VERSION 5.8 ;
BUSBITCHARS "[]" ;
DIVIDERCHAR "/" ;

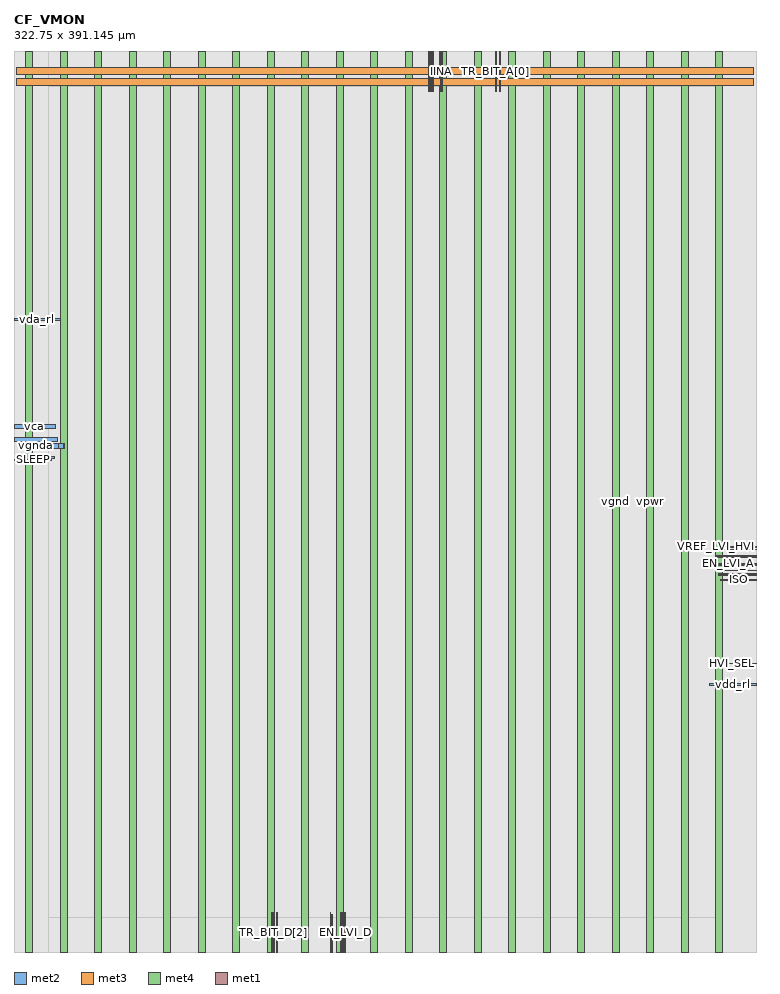
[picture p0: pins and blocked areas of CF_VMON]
MACRO CF_VMON
  CLASS BLOCK ;
  ORIGIN 0 0 ;
  FOREIGN CF_VMON 0 0 ;
  SIZE 322.75 BY 391.145 ;
  PIN vgnd
    DIRECTION INPUT ;
    USE GROUND ;
    PORT
      LAYER met2 ;
        RECT 15 218.8 19.265 220.8 ;
        RECT 15 218.8 21.79 220.8 ;
      LAYER met3 ;
        RECT 21.31 218.8 21.79 220.8 ;
        RECT 1.23 376.645 321.52 379.745 ;
      LAYER met4 ;
        RECT 20 0 23.1 391.145 ;
        RECT 50 0 53.1 391.145 ;
        RECT 80 0 83.1 391.145 ;
        RECT 110 0 113.1 391.145 ;
        RECT 140 0 143.1 391.145 ;
        RECT 170 0 173.1 391.145 ;
        RECT 200 0 203.1 391.145 ;
        RECT 230 0 233.1 391.145 ;
        RECT 260 0 263.1 391.145 ;
        RECT 290 0 293.1 391.145 ;
    END
  END vgnd
  PIN vgnda
    DIRECTION INOUT ;
    USE SIGNAL ;
    PORT
      LAYER met2 ;
        RECT 0 221.72 19.1 223.72 ;
    END
  END vgnda
  PIN vdd_rl
    DIRECTION INOUT ;
    USE SIGNAL ;
    PORT
      LAYER met2 ;
        RECT 302.455 115.665 322.75 116.565 ;
    END
  END vdd_rl
  PIN vda_rl
    DIRECTION INOUT ;
    USE SIGNAL ;
    PORT
      LAYER met2 ;
        RECT 0 274.325 20.39 275.225 ;
    END
  END vda_rl
  PIN vpwr
    DIRECTION INPUT ;
    USE POWER ;
    PORT
      LAYER met2 ;
        RECT 15 214.435 17.475 215.395 ;
        RECT 6.31 214.435 17.475 215.395 ;
      LAYER met3 ;
        RECT 6.31 214.435 6.79 215.395 ;
        RECT 1.23 381.445 321.52 384.545 ;
      LAYER met4 ;
        RECT 5 0 8.1 391.145 ;
        RECT 35 0 38.1 391.145 ;
        RECT 65 0 68.1 391.145 ;
        RECT 95 0 98.1 391.145 ;
        RECT 125 0 128.1 391.145 ;
        RECT 155 0 158.1 391.145 ;
        RECT 185 0 188.1 391.145 ;
        RECT 215 0 218.1 391.145 ;
        RECT 245 0 248.1 391.145 ;
        RECT 275 0 278.1 391.145 ;
        RECT 305 0 308.1 391.145 ;
    END
  END vpwr
  PIN vca
    DIRECTION INOUT ;
    USE SIGNAL ;
    PORT
      LAYER met2 ;
        RECT 0 227.51 18.245 229.43 ;
    END
  END vca
  PIN PRES_D_OUT
    DIRECTION OUTPUT ;
    USE SIGNAL ;
    PORT
      LAYER met2 ;
        RECT 305.335 171.55 322.75 171.79 ;
    END
  END PRES_D_OUT
  PIN PRES_A_OUT
    DIRECTION OUTPUT ;
    USE SIGNAL ;
    PORT
      LAYER met2 ;
        RECT 305.4 168.595 322.75 168.835 ;
    END
  END PRES_A_OUT
  PIN LVI_D_OUT
    DIRECTION OUTPUT ;
    USE SIGNAL ;
    PORT
      LAYER met2 ;
        RECT 306.09 165.64 322.75 165.88 ;
    END
  END LVI_D_OUT
  PIN LVI_A_OUT
    DIRECTION OUTPUT ;
    USE SIGNAL ;
    PORT
      LAYER met2 ;
        RECT 306.055 163.7 322.75 163.94 ;
    END
  END LVI_A_OUT
  PIN HVI_OUT
    DIRECTION OUTPUT ;
    USE SIGNAL ;
    PORT
      LAYER met2 ;
        RECT 306.055 164.16 322.75 164.4 ;
    END
  END HVI_OUT
  PIN TR_BIT_D[3]
    DIRECTION INPUT ;
    USE SIGNAL ;
    PORT
      LAYER met1 ;
        RECT 112.115 0 112.255 17.15 ;
    END
  END TR_BIT_D[3]
  PIN TR_BIT_D[2]
    DIRECTION INPUT ;
    USE SIGNAL ;
    PORT
      LAYER met1 ;
        RECT 112.555 0 112.695 17.15 ;
    END
  END TR_BIT_D[2]
  PIN TR_BIT_D[1]
    DIRECTION INPUT ;
    USE SIGNAL ;
    PORT
      LAYER met1 ;
        RECT 113.875 0 114.015 17.15 ;
    END
  END TR_BIT_D[1]
  PIN TR_BIT_D[0]
    DIRECTION INPUT ;
    USE SIGNAL ;
    PORT
      LAYER met1 ;
        RECT 114.315 0 114.455 17.15 ;
    END
  END TR_BIT_D[0]
  PIN TR_BIT_A[3]
    DIRECTION INPUT ;
    USE SIGNAL ;
    PORT
      LAYER met1 ;
        RECT 211.44 373.995 211.58 391.145 ;
    END
  END TR_BIT_A[3]
  PIN TR_BIT_A[2]
    DIRECTION INPUT ;
    USE SIGNAL ;
    PORT
      LAYER met1 ;
        RECT 211 373.995 211.14 391.145 ;
    END
  END TR_BIT_A[2]
  PIN TR_BIT_A[1]
    DIRECTION INPUT ;
    USE SIGNAL ;
    PORT
      LAYER met1 ;
        RECT 209.68 373.995 209.82 391.145 ;
    END
  END TR_BIT_A[1]
  PIN TR_BIT_A[0]
    DIRECTION INPUT ;
    USE SIGNAL ;
    PORT
      LAYER met1 ;
        RECT 209.24 373.995 209.38 391.145 ;
    END
  END TR_BIT_A[0]
  PIN PD
    DIRECTION INPUT ;
    USE SIGNAL ;
    PORT
      LAYER met2 ;
        RECT 307.25 161.265 322.75 161.465 ;
    END
  END PD
  PIN LVI_D_SEL[3]
    DIRECTION INPUT ;
    USE SIGNAL ;
    PORT
      LAYER met1 ;
        RECT 143.375 0 143.575 17.15 ;
    END
  END LVI_D_SEL[3]
  PIN LVI_D_SEL[2]
    DIRECTION INPUT ;
    USE SIGNAL ;
    PORT
      LAYER met1 ;
        RECT 142.945 0 143.145 17.15 ;
    END
  END LVI_D_SEL[2]
  PIN LVI_D_SEL[1]
    DIRECTION INPUT ;
    USE SIGNAL ;
    PORT
      LAYER met1 ;
        RECT 142.515 0 142.715 17.15 ;
    END
  END LVI_D_SEL[1]
  PIN LVI_D_SEL[0]
    DIRECTION INPUT ;
    USE SIGNAL ;
    PORT
      LAYER met1 ;
        RECT 142.085 0 142.285 17.15 ;
    END
  END LVI_D_SEL[0]
  PIN LVI_A_SEL[3]
    DIRECTION INPUT ;
    USE SIGNAL ;
    PORT
      LAYER met1 ;
        RECT 180.12 373.995 180.32 391.145 ;
    END
  END LVI_A_SEL[3]
  PIN LVI_A_SEL[2]
    DIRECTION INPUT ;
    USE SIGNAL ;
    PORT
      LAYER met1 ;
        RECT 180.55 373.995 180.75 391.145 ;
    END
  END LVI_A_SEL[2]
  PIN LVI_A_SEL[1]
    DIRECTION INPUT ;
    USE SIGNAL ;
    PORT
      LAYER met1 ;
        RECT 180.98 373.995 181.18 391.145 ;
    END
  END LVI_A_SEL[1]
  PIN ISO
    DIRECTION INPUT ;
    USE SIGNAL ;
    PORT
      LAYER met2 ;
        RECT 307.26 161.695 322.75 161.895 ;
    END
  END ISO
  PIN VREF_PRES
    DIRECTION INPUT ;
    USE SIGNAL ;
    PORT
      LAYER met1 ;
        RECT 306.19 174.73 322.75 174.93 ;
    END
  END VREF_PRES
  PIN VREF_LVI_HVI
    DIRECTION INPUT ;
    USE SIGNAL ;
    PORT
      LAYER met1 ;
        RECT 306.405 175.93 322.75 176.13 ;
    END
  END VREF_LVI_HVI
  PIN SLEEP
    DIRECTION INPUT ;
    USE SIGNAL ;
    PORT
      LAYER met2 ;
        RECT 0 213.745 16.13 214.005 ;
    END
  END SLEEP
  PIN en_iso_vcca
    DIRECTION INPUT ;
    USE SIGNAL ;
    PORT
      LAYER met2 ;
        RECT 305.98 167.855 322.75 168.095 ;
    END
  END en_iso_vcca
  PIN HVI_SEL
    DIRECTION INPUT ;
    USE SIGNAL ;
    PORT
      LAYER met2 ;
        RECT 307.375 125.215 322.75 125.415 ;
    END
  END HVI_SEL
  PIN EN_HVI_A
    DIRECTION INPUT ;
    USE SIGNAL ;
    PORT
      LAYER met1 ;
        RECT 181.955 374 182.155 391.145 ;
    END
  END EN_HVI_A
  PIN EN_LVI_A
    DIRECTION INPUT ;
    USE SIGNAL ;
    PORT
      LAYER met2 ;
        RECT 305.335 172.24 322.75 172.44 ;
    END
  END EN_LVI_A
  PIN EN_LVI_D
    DIRECTION INPUT ;
    USE SIGNAL ;
    PORT
      LAYER met1 ;
        RECT 143.805 0 144.005 17.15 ;
    END
  END EN_LVI_D
  PIN EN_PRES_A
    DIRECTION INPUT ;
    USE SIGNAL ;
    PORT
      LAYER met1 ;
        RECT 185.995 373.995 186.195 391.145 ;
    END
  END EN_PRES_A
  PIN EN_PRES_D
    DIRECTION INPUT ;
    USE SIGNAL ;
    PORT
      LAYER met1 ;
        RECT 137.5 0 137.7 17.15 ;
    END
  END EN_PRES_D
  PIN IINA
    DIRECTION INPUT ;
    USE SIGNAL ;
    PORT
      LAYER met1 ;
        RECT 185.46 374.13 185.76 391.145 ;
    END
  END IINA
  PIN IIND
    DIRECTION INPUT ;
    USE SIGNAL ;
    PORT
      LAYER met1 ;
        RECT 137.935 0 138.235 16.24 ;
    END
  END IIND
  PIN LVI_A_SEL[0]
    DIRECTION INPUT ;
    USE SIGNAL ;
    PORT
      LAYER met1 ;
        RECT 181.41 373.995 181.61 391.145 ;
    END
  END LVI_A_SEL[0]
  OBS
    LAYER li1 ;
      RECT 0 0 322.75 391.145 ;
    LAYER met1 ;
      RECT 0 0 15 391.145 ;
      RECT 307.75 0 322.75 174.73 ;
      RECT 307.75 174.93 322.75 175.93 ;
      RECT 307.75 176.13 322.75 391.145 ;
      RECT 15 0 112.115 15 ;
      RECT 112.255 0 112.555 15 ;
      RECT 112.695 0 113.875 15 ;
      RECT 114.015 0 114.315 15 ;
      RECT 114.455 0 137.5 15 ;
      RECT 137.7 0 137.935 15 ;
      RECT 138.235 0 142.085 15 ;
      RECT 142.285 0 142.515 15 ;
      RECT 142.715 0 142.945 15 ;
      RECT 143.145 0 143.375 15 ;
      RECT 143.575 0 143.805 15 ;
      RECT 144.005 0 307.75 15 ;
      RECT 15 376.145 180.12 391.145 ;
      RECT 180.32 376.145 180.55 391.145 ;
      RECT 180.75 376.145 180.98 391.145 ;
      RECT 181.18 376.145 181.41 391.145 ;
      RECT 181.61 376.145 181.955 391.145 ;
      RECT 182.155 376.145 185.46 391.145 ;
      RECT 185.76 376.145 185.995 391.145 ;
      RECT 186.195 376.145 209.24 391.145 ;
      RECT 209.38 376.145 209.68 391.145 ;
      RECT 209.82 376.145 211 391.145 ;
      RECT 211.14 376.145 211.44 391.145 ;
      RECT 211.58 376.145 307.75 391.145 ;
    LAYER met2 ;
      RECT 0 0 6.31 213.745 ;
      RECT 0 214.005 6.31 221.72 ;
      RECT 0 223.72 6.31 227.51 ;
      RECT 0 229.43 6.31 274.325 ;
      RECT 0 275.225 6.31 391.145 ;
      RECT 6.31 0 15 213.745 ;
      RECT 6.31 214.005 15 214.435 ;
      RECT 6.31 215.395 15 221.72 ;
      RECT 6.31 223.72 15 227.51 ;
      RECT 6.31 229.43 15 274.325 ;
      RECT 6.31 275.225 15 391.145 ;
      RECT 307.75 0 322.75 115.665 ;
      RECT 307.75 116.565 322.75 125.215 ;
      RECT 307.75 125.415 322.75 161.265 ;
      RECT 307.75 161.465 322.75 161.695 ;
      RECT 307.75 161.895 322.75 163.7 ;
      RECT 307.75 163.94 322.75 164.16 ;
      RECT 307.75 164.4 322.75 165.64 ;
      RECT 307.75 165.88 322.75 167.855 ;
      RECT 307.75 168.095 322.75 168.595 ;
      RECT 307.75 168.835 322.75 171.55 ;
      RECT 307.75 171.79 322.75 172.24 ;
      RECT 307.75 172.44 322.75 391.145 ;
      RECT 15 0 307.75 15 ;
      RECT 15 376.145 307.75 391.145 ;
  END
END CF_VMON

END LIBRARY
